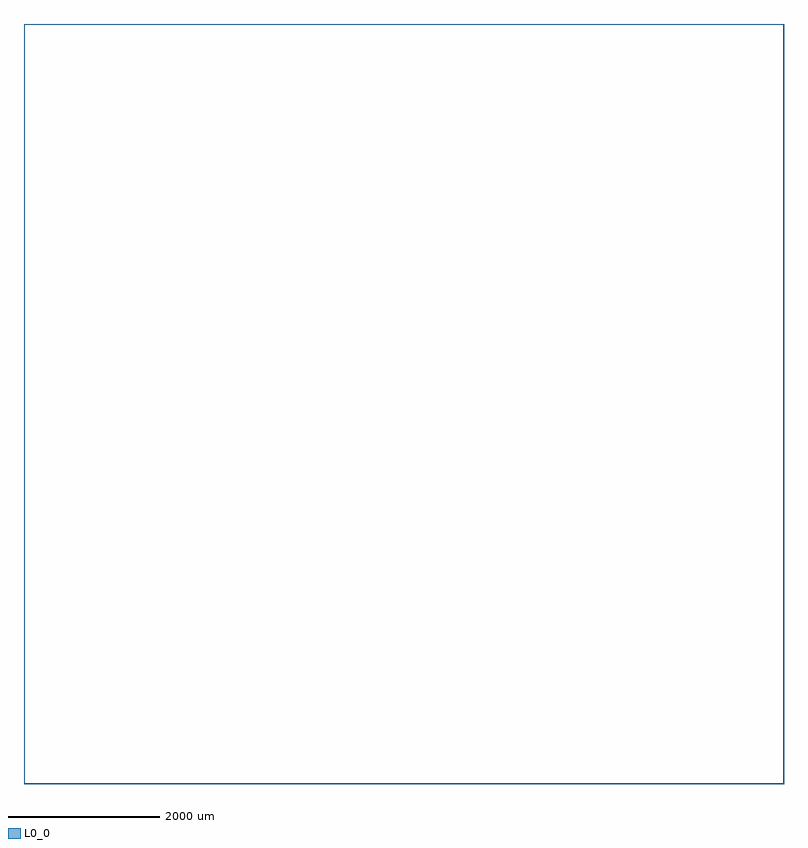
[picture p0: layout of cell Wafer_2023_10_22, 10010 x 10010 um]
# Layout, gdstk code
import gdstk
lib = gdstk.Library(unit=1e-6, precision=1e-09)
def P(c, l, *ps):  # polygons
    for p in ps: c.add(gdstk.Polygon(p, *l))
L0_0 = (0, 0)

wafer_2023_10_22 = lib.new_cell('Wafer_2023_10_22')
P(wafer_2023_10_22, L0_0, [(10003,10003),(-3,10003),(-3,0),(0,0),(0,10000),(10000,10000),(10000,0),(0,0),(-3,0),(-3,-3),(10003,-3)],
  [(10003,10004),(-3,10004),(-3,1),(0,1),(0,10000),(10000,10000),(10000,1),(0,1),(-3,1),(-3,-2),(10003,-2)],
  [(10003,10005),(-3,10005),(-3,2),(0,2),(0,10000),(10000,10000),(10000,2),(0,2),(-3,2),(-3,-1),(10003,-1)],
  [(10003,10006),(-3,10006),(-3,3),(0,3),(0,10000),(10000,10000),(10000,3),(0,3),(-3,3),(-3,0),(10003,0)],
  [(10003,10007),(-3,10007),(-3,4),(0,4),(0,10000),(10000,10000),(10000,4),(0,4),(-3,4),(-3,1),(10003,1)],
  [(10004,10003),(-2,10003),(-2,0),(1,0),(1,10000),(10000,10000),(10000,0),(1,0),(-2,0),(-2,-3),(10004,-3)],
  [(10004,10004),(-2,10004),(-2,1),(1,1),(1,10000),(10000,10000),(10000,1),(1,1),(-2,1),(-2,-2),(10004,-2)],
  [(10004,10005),(-2,10005),(-2,2),(1,2),(1,10000),(10000,10000),(10000,2),(1,2),(-2,2),(-2,-1),(10004,-1)],
  [(10004,10006),(-2,10006),(-2,3),(1,3),(1,10000),(10000,10000),(10000,3),(1,3),(-2,3),(-2,0),(10004,0)],
  [(10004,10007),(-2,10007),(-2,4),(1,4),(1,10000),(10000,10000),(10000,4),(1,4),(-2,4),(-2,1),(10004,1)],
  [(10005,10003),(-1,10003),(-1,0),(2,0),(2,10000),(10000,10000),(10000,0),(2,0),(-1,0),(-1,-3),(10005,-3)],
  [(10005,10004),(-1,10004),(-1,1),(2,1),(2,10000),(10000,10000),(10000,1),(2,1),(-1,1),(-1,-2),(10005,-2)],
  [(10005,10005),(-1,10005),(-1,2),(2,2),(2,10000),(10000,10000),(10000,2),(2,2),(-1,2),(-1,-1),(10005,-1)],
  [(10005,10006),(-1,10006),(-1,3),(2,3),(2,10000),(10000,10000),(10000,3),(2,3),(-1,3),(-1,0),(10005,0)],
  [(10005,10007),(-1,10007),(-1,4),(2,4),(2,10000),(10000,10000),(10000,4),(2,4),(-1,4),(-1,1),(10005,1)],
  [(10006,10003),(0,10003),(0,0),(3,0),(3,10000),(10000,10000),(10000,0),(3,0),(0,0),(0,-3),(10006,-3)],
  [(10006,10004),(0,10004),(0,1),(3,1),(3,10000),(10000,10000),(10000,1),(3,1),(0,1),(0,-2),(10006,-2)],
  [(10006,10005),(0,10005),(0,2),(3,2),(3,10000),(10000,10000),(10000,2),(3,2),(0,2),(0,-1),(10006,-1)],
  [(10006,10006),(0,10006),(0,3),(3,3),(3,10000),(10000,10000),(10000,3),(3,3),(0,3),(0,0),(10006,0)],
  [(10006,10007),(0,10007),(0,4),(3,4),(3,10000),(10000,10000),(10000,4),(3,4),(0,4),(0,1),(10006,1)],
  [(10007,10003),(1,10003),(1,0),(4,0),(4,10000),(10000,10000),(10000,0),(4,0),(1,0),(1,-3),(10007,-3)],
  [(10007,10004),(1,10004),(1,1),(4,1),(4,10000),(10000,10000),(10000,1),(4,1),(1,1),(1,-2),(10007,-2)],
  [(10007,10005),(1,10005),(1,2),(4,2),(4,10000),(10000,10000),(10000,2),(4,2),(1,2),(1,-1),(10007,-1)],
  [(10007,10006),(1,10006),(1,3),(4,3),(4,10000),(10000,10000),(10000,3),(4,3),(1,3),(1,0),(10007,0)],
  [(10007,10007),(1,10007),(1,4),(4,4),(4,10000),(10000,10000),(10000,4),(4,4),(1,4),(1,1),(10007,1)])

lib.write_gds('Wafer_2023_10_22.gds')
